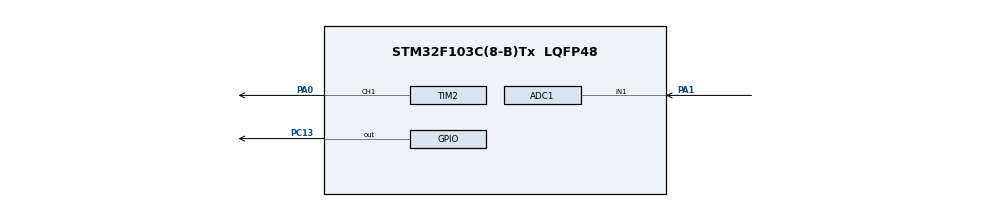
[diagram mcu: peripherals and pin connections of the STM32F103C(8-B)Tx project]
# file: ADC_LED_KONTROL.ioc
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ADC1.Channel-0\#ChannelRegularConversion=ADC_CHANNEL_1
ADC1.NbrOfConversionFlag=1
ADC1.Rank-0\#ChannelRegularConversion=1
ADC1.SamplingTime-0\#ChannelRegularConversion=ADC_SAMPLETIME_1CYCLE_5
ADC1.master=1
Mcu.Family=STM32F1
Mcu.Name=STM32F103C(8-B)Tx
Mcu.Package=LQFP48
NVIC.ADC1_2_IRQn=true\:0\:0\:false\:false\:true\:true\:true
NVIC.PriorityGroup=NVIC_PRIORITYGROUP_4
PA0-WKUP.Signal=S_TIM2_CH1_ETR
PA1.Signal=ADCx_IN1
PC13-TAMPER-RTC.Signal=GPIO_Output
PD0-OSC_IN.Mode=HSE-External-Oscillator
PD0-OSC_IN.Signal=RCC_OSC_IN
PD1-OSC_OUT.Mode=HSE-External-Oscillator
PD1-OSC_OUT.Signal=RCC_OSC_OUT
ProjectManager.HeapSize=0x200
ProjectManager.StackSize=0x400
ProjectManager.TargetToolchain=MDK-ARM V5.27
RCC.AHBFreq_Value=14000000
RCC.APB1Freq_Value=14000000
RCC.APB1TimFreq_Value=14000000
RCC.APB2Freq_Value=14000000
RCC.APB2TimFreq_Value=14000000
RCC.HCLKFreq_Value=14000000
RCC.HSE_VALUE=14000000
RCC.SYSCLKFreq_VALUE=14000000
RCC.SYSCLKSource=RCC_SYSCLKSOURCE_HSE
RCC.USBFreq_Value=8000000
SH.ADCx_IN1.0=ADC1_IN1,IN1
SH.S_TIM2_CH1_ETR.0=TIM2_CH1,PWM Generation1 CH1
TIM2.AutoReloadPreload=TIM_AUTORELOAD_PRELOAD_ENABLE
TIM2.Channel-PWM\ Generation1\ CH1=TIM_CHANNEL_1
VP_SYS_VS_ND.Mode=No_Debug
VP_TIM2_VS_ClockSourceINT.Mode=Internal
board=custom

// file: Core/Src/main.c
/* USER CODE BEGIN Header */
/**
  ******************************************************************************
  * @file           : main.c
  * @brief          : Main program body
  ******************************************************************************
  * @attention
  *
  * <h2><center>&copy; Copyright (c) 2021 STMicroelectronics.
  * All rights reserved.</center></h2>
  *
  * This software component is licensed by ST under BSD 3-Clause license,
  * the "License"; You may not use this file except in compliance with the
  * License. You may obtain a copy of the License at:
  *                        opensource.org/licenses/BSD-3-Clause
  *
  ******************************************************************************
  */
/* USER CODE END Header */
#include "main.h"
#include "adc.h"
#include "tim.h"
#include "gpio.h"

void SystemClock_Config(void);

int main(void)
{

  /* MCU Configuration--------------------------------------------------------*/

  /* Reset of all peripherals, Initializes the Flash interface and the Systick. */
  HAL_Init();

  /* Configure the system clock */
  SystemClock_Config();

  /* Initialize all configured peripherals */
  MX_GPIO_Init();
  MX_ADC1_Init();
  MX_TIM2_Init();

  /* Infinite loop */
  while (1)
  {

  }
}

void SystemClock_Config(void)
{
  RCC_OscInitTypeDef RCC_OscInitStruct = {0};
  RCC_ClkInitTypeDef RCC_ClkInitStruct = {0};
  RCC_PeriphCLKInitTypeDef PeriphClkInit = {0};

  /** Initializes the RCC Oscillators according to the specified parameters
  * in the RCC_OscInitTypeDef structure.
  */
  /** Initializes the CPU, AHB and APB buses clocks
  */
   RCC_OscInitStruct.OscillatorType = RCC_OSCILLATORTYPE_HSE;
  RCC_OscInitStruct.HSEState = RCC_HSE_ON;
  RCC_OscInitStruct.HSEPredivValue = RCC_HSE_PREDIV_DIV1;
  RCC_OscInitStruct.HSIState = RCC_HSI_ON;
  RCC_OscInitStruct.PLL.PLLState = RCC_PLL_ON;
  RCC_OscInitStruct.PLL.PLLSource = RCC_PLLSOURCE_HSE;
  RCC_OscInitStruct.PLL.PLLMUL = RCC_PLL_MUL9;
  if (HAL_RCC_OscConfig(&RCC_OscInitStruct) != HAL_OK)

  {
    Error_Handler();

  }
	RCC_ClkInitStruct.ClockType = RCC_CLOCKTYPE_HCLK|RCC_CLOCKTYPE_SYSCLK
                              |RCC_CLOCKTYPE_PCLK1|RCC_CLOCKTYPE_PCLK2;
  RCC_ClkInitStruct.SYSCLKSource = RCC_SYSCLKSOURCE_PLLCLK;
  RCC_ClkInitStruct.AHBCLKDivider = RCC_SYSCLK_DIV1;
  RCC_ClkInitStruct.APB1CLKDivider = RCC_HCLK_DIV2;
  RCC_ClkInitStruct.APB2CLKDivider = RCC_HCLK_DIV1;

  if (HAL_RCC_ClockConfig(&RCC_ClkInitStruct, FLASH_LATENCY_2) != HAL_OK)
  {
    Error_Handler();
	}
  PeriphClkInit.PeriphClockSelection = RCC_PERIPHCLK_ADC;
  PeriphClkInit.AdcClockSelection = RCC_ADCPCLK2_DIV6;
  if (HAL_RCCEx_PeriphCLKConfig(&PeriphClkInit) != HAL_OK)
  {
    Error_Handler();
  }
}

void Error_Handler(void)
{
  __disable_irq();
  while (1)
  {
  }
}

/************************ (C) COPYRIGHT STMicroelectronics *****END OF FILE****/
